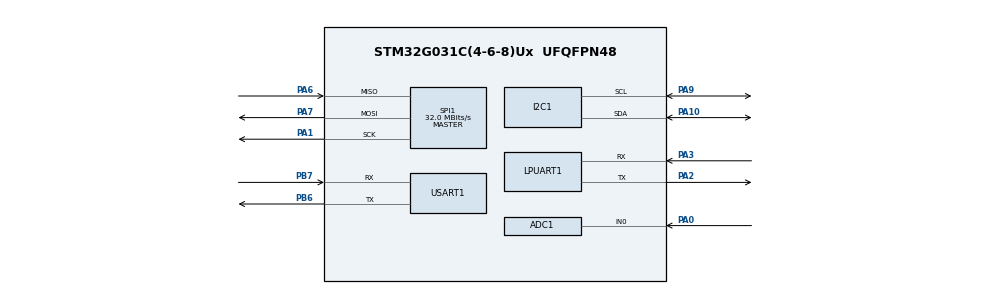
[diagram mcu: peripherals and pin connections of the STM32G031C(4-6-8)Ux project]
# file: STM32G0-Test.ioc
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ADC1.Channel-0\#ChannelRegularConversion=ADC_CHANNEL_0
ADC1.NbrOfConversionFlag=1
ADC1.Rank-0\#ChannelRegularConversion=1
ADC1.SamplingTime-0\#ChannelRegularConversion=ADC_SAMPLINGTIME_COMMON_1
ADC1.SelectedChannel=ADC_CHANNEL_0
ADC1.master=1
Dma.MEMTOMEM.0.Direction=DMA_MEMORY_TO_MEMORY
Dma.MEMTOMEM.0.EventEnable=DISABLE
Dma.MEMTOMEM.0.Instance=DMA1_Channel1
Dma.MEMTOMEM.0.MemDataAlignment=DMA_MDATAALIGN_BYTE
Dma.MEMTOMEM.0.MemInc=DMA_MINC_ENABLE
Dma.MEMTOMEM.0.Mode=DMA_NORMAL
Dma.MEMTOMEM.0.PeriphDataAlignment=DMA_PDATAALIGN_BYTE
Dma.MEMTOMEM.0.PeriphInc=DMA_PINC_ENABLE
Dma.MEMTOMEM.0.Polarity=HAL_DMAMUX_REQ_GEN_RISING
Dma.MEMTOMEM.0.Priority=DMA_PRIORITY_LOW
Dma.MEMTOMEM.0.RequestNumber=1
Dma.MEMTOMEM.0.SignalID=NONE
Dma.MEMTOMEM.0.SyncEnable=DISABLE
Dma.MEMTOMEM.0.SyncPolarity=HAL_DMAMUX_SYNC_NO_EVENT
Dma.MEMTOMEM.0.SyncRequestNumber=1
Dma.MEMTOMEM.0.SyncSignalID=NONE
Dma.Request0=MEMTOMEM
I2C1.Timing=0x10707DBC
Mcu.Family=STM32G0
Mcu.Name=STM32G031C(4-6-8)Ux
Mcu.Package=UFQFPN48
PA0.Mode=IN0
PA0.Signal=ADC1_IN0
PA1.Mode=Full_Duplex_Master
PA1.Signal=SPI1_SCK
PA10.Mode=I2C
PA10.Signal=I2C1_SDA
PA2.Mode=Asynchronous
PA2.Signal=LPUART1_TX
PA3.Mode=Asynchronous
PA3.Signal=LPUART1_RX
PA6.Mode=Full_Duplex_Master
PA6.Signal=SPI1_MISO
PA7.Mode=Full_Duplex_Master
PA7.Signal=SPI1_MOSI
PA9.Mode=I2C
PA9.Signal=I2C1_SCL
PB6.Mode=Asynchronous
PB6.Signal=USART1_TX
PB7.Mode=Asynchronous
PB7.Signal=USART1_RX
PF0-OSC_IN\ (PF0).Mode=HSE-External-Oscillator
PF0-OSC_IN\ (PF0).Signal=RCC_OSC_IN
PF1-OSC_OUT\ (PF1).Mode=HSE-External-Oscillator
PF1-OSC_OUT\ (PF1).Signal=RCC_OSC_OUT
ProjectManager.HeapSize=0x200
ProjectManager.StackSize=0x400
ProjectManager.TargetToolchain=STM32CubeIDE
RCC.ADCCLockSelection=RCC_ADCCLKSOURCE_HSI
RCC.ADCFreq_Value=16000000
RCC.AHBFreq_Value=64000000
RCC.CortexFreq_Value=64000000
RCC.EXTERNAL_CLOCK_VALUE=12288000
RCC.HCLKFreq_Value=64000000
RCC.HSE_VALUE=8000000
RCC.HSI_VALUE=16000000
RCC.LSE_VALUE=32768
RCC.SYSCLKFreq_VALUE=64000000
RCC.SYSCLKSource=RCC_SYSCLKSOURCE_PLLCLK
RCC.VCOOutputFreq_Value=128000000
SPI1.CalculateBaudRate=32.0 MBits/s
SPI1.Direction=SPI_DIRECTION_2LINES
SPI1.Mode=SPI_MODE_MASTER
SPI1.VirtualType=VM_MASTER
USART1.VirtualMode-Asynchronous=VM_ASYNC
VP_CRC_VS_CRC.Mode=CRC_Activate
VP_IWDG_VS_IWDG.Mode=IWDG_Activate
VP_RTC_VS_RTC_Activate.Mode=RTC_Enabled
VP_TIM1_VS_ClockSourceINT.Mode=Internal
VP_TIM1_VS_ClockSourceITR.Mode=TriggerSource_ITR0
VP_TIM1_VS_ControllerModeReset.Mode=Reset Mode
board=custom

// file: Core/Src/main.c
/* USER CODE BEGIN Header */
/**
  ******************************************************************************
  * @file           : main.c
  * @brief          : Main program body
  ******************************************************************************
  * @attention
  *
  * Copyright (c) 2022 STMicroelectronics.
  * All rights reserved.
  *
  * This software is licensed under terms that can be found in the LICENSE file
  * in the root directory of this software component.
  * If no LICENSE file comes with this software, it is provided AS-IS.
  *
  ******************************************************************************
  */
/* USER CODE END Header */
#include "main.h"

ADC_HandleTypeDef hadc1;

CRC_HandleTypeDef hcrc;

I2C_HandleTypeDef hi2c1;

IWDG_HandleTypeDef hiwdg;

UART_HandleTypeDef hlpuart1;
UART_HandleTypeDef huart1;

RTC_HandleTypeDef hrtc;

SPI_HandleTypeDef hspi1;

TIM_HandleTypeDef htim1;

DMA_HandleTypeDef hdma_memtomem_dma1_channel1;

void SystemClock_Config(void);
static void MX_DMA_Init(void);
static void MX_GPIO_Init(void);
static void MX_ADC1_Init(void);
static void MX_CRC_Init(void);
static void MX_I2C1_Init(void);
static void MX_IWDG_Init(void);
static void MX_LPUART1_UART_Init(void);
static void MX_USART1_UART_Init(void);
static void MX_RTC_Init(void);
static void MX_SPI1_Init(void);
static void MX_TIM1_Init(void);

int main(void)
{

  /* MCU Configuration--------------------------------------------------------*/

  /* Reset of all peripherals, Initializes the Flash interface and the Systick. */
  HAL_Init();

  /* Configure the system clock */
  SystemClock_Config();

  /* Initialize all configured peripherals */
  MX_DMA_Init();
  MX_GPIO_Init();
  MX_ADC1_Init();
  MX_CRC_Init();
  MX_I2C1_Init();
  MX_IWDG_Init();
  MX_LPUART1_UART_Init();
  MX_USART1_UART_Init();
  MX_RTC_Init();
  MX_SPI1_Init();
  MX_TIM1_Init();

  /* Infinite loop */
  while (1)
  {

  }
}

void SystemClock_Config(void)
{
  RCC_OscInitTypeDef RCC_OscInitStruct = {0};
  RCC_ClkInitTypeDef RCC_ClkInitStruct = {0};

  /** Configure the main internal regulator output voltage
  */
  HAL_PWREx_ControlVoltageScaling(PWR_REGULATOR_VOLTAGE_SCALE1);
  /** Initializes the RCC Oscillators according to the specified parameters
  * in the RCC_OscInitTypeDef structure.
  */
  RCC_OscInitStruct.OscillatorType = RCC_OSCILLATORTYPE_HSI|RCC_OSCILLATORTYPE_LSI;
  RCC_OscInitStruct.HSIState = RCC_HSI_ON;
  RCC_OscInitStruct.HSIDiv = RCC_HSI_DIV1;
  RCC_OscInitStruct.HSICalibrationValue = RCC_HSICALIBRATION_DEFAULT;
  RCC_OscInitStruct.LSIState = RCC_LSI_ON;
  RCC_OscInitStruct.PLL.PLLState = RCC_PLL_NONE;
  if (HAL_RCC_OscConfig(&RCC_OscInitStruct) != HAL_OK)
  {
    Error_Handler();
  }
  /** Initializes the CPU, AHB and APB buses clocks
  */
  RCC_ClkInitStruct.ClockType = RCC_CLOCKTYPE_HCLK|RCC_CLOCKTYPE_SYSCLK
                              |RCC_CLOCKTYPE_PCLK1;
  RCC_ClkInitStruct.SYSCLKSource = RCC_SYSCLKSOURCE_HSI;
  RCC_ClkInitStruct.AHBCLKDivider = RCC_SYSCLK_DIV1;
  RCC_ClkInitStruct.APB1CLKDivider = RCC_HCLK_DIV1;

  if (HAL_RCC_ClockConfig(&RCC_ClkInitStruct, FLASH_LATENCY_0) != HAL_OK)
  {
    Error_Handler();
  }
}

static void MX_ADC1_Init(void)
{

  ADC_ChannelConfTypeDef sConfig = {0};

  /** Configure the global features of the ADC (Clock, Resolution, Data Alignment and number of conversion)
  */
  hadc1.Instance = ADC1;
  hadc1.Init.ClockPrescaler = ADC_CLOCK_SYNC_PCLK_DIV2;
  hadc1.Init.Resolution = ADC_RESOLUTION_12B;
  hadc1.Init.DataAlign = ADC_DATAALIGN_RIGHT;
  hadc1.Init.ScanConvMode = ADC_SCAN_DISABLE;
  hadc1.Init.EOCSelection = ADC_EOC_SINGLE_CONV;
  hadc1.Init.LowPowerAutoWait = DISABLE;
  hadc1.Init.LowPowerAutoPowerOff = DISABLE;
  hadc1.Init.ContinuousConvMode = DISABLE;
  hadc1.Init.NbrOfConversion = 1;
  hadc1.Init.DiscontinuousConvMode = DISABLE;
  hadc1.Init.ExternalTrigConv = ADC_SOFTWARE_START;
  hadc1.Init.ExternalTrigConvEdge = ADC_EXTERNALTRIGCONVEDGE_NONE;
  hadc1.Init.DMAContinuousRequests = DISABLE;
  hadc1.Init.Overrun = ADC_OVR_DATA_PRESERVED;
  hadc1.Init.SamplingTimeCommon1 = ADC_SAMPLETIME_1CYCLE_5;
  hadc1.Init.SamplingTimeCommon2 = ADC_SAMPLETIME_1CYCLE_5;
  hadc1.Init.OversamplingMode = DISABLE;
  hadc1.Init.TriggerFrequencyMode = ADC_TRIGGER_FREQ_HIGH;
  if (HAL_ADC_Init(&hadc1) != HAL_OK)
  {
    Error_Handler();
  }
  /** Configure Regular Channel
  */
  sConfig.Channel = ADC_CHANNEL_0;
  sConfig.Rank = ADC_REGULAR_RANK_1;
  sConfig.SamplingTime = ADC_SAMPLINGTIME_COMMON_1;
  if (HAL_ADC_ConfigChannel(&hadc1, &sConfig) != HAL_OK)
  {
    Error_Handler();
  }

}

static void MX_CRC_Init(void)
{

  hcrc.Instance = CRC;
  hcrc.Init.DefaultPolynomialUse = DEFAULT_POLYNOMIAL_ENABLE;
  hcrc.Init.DefaultInitValueUse = DEFAULT_INIT_VALUE_ENABLE;
  hcrc.Init.InputDataInversionMode = CRC_INPUTDATA_INVERSION_NONE;
  hcrc.Init.OutputDataInversionMode = CRC_OUTPUTDATA_INVERSION_DISABLE;
  hcrc.InputDataFormat = CRC_INPUTDATA_FORMAT_BYTES;
  if (HAL_CRC_Init(&hcrc) != HAL_OK)
  {
    Error_Handler();
  }

}

static void MX_I2C1_Init(void)
{

  hi2c1.Instance = I2C1;
  hi2c1.Init.Timing = 0x00303D5B;
  hi2c1.Init.OwnAddress1 = 0;
  hi2c1.Init.AddressingMode = I2C_ADDRESSINGMODE_7BIT;
  hi2c1.Init.DualAddressMode = I2C_DUALADDRESS_DISABLE;
  hi2c1.Init.OwnAddress2 = 0;
  hi2c1.Init.OwnAddress2Masks = I2C_OA2_NOMASK;
  hi2c1.Init.GeneralCallMode = I2C_GENERALCALL_DISABLE;
  hi2c1.Init.NoStretchMode = I2C_NOSTRETCH_DISABLE;
  if (HAL_I2C_Init(&hi2c1) != HAL_OK)
  {
    Error_Handler();
  }
  /** Configure Analogue filter
  */
  if (HAL_I2CEx_ConfigAnalogFilter(&hi2c1, I2C_ANALOGFILTER_ENABLE) != HAL_OK)
  {
    Error_Handler();
  }
  /** Configure Digital filter
  */
  if (HAL_I2CEx_ConfigDigitalFilter(&hi2c1, 0) != HAL_OK)
  {
    Error_Handler();
  }

}

static void MX_IWDG_Init(void)
{

  hiwdg.Instance = IWDG;
  hiwdg.Init.Prescaler = IWDG_PRESCALER_4;
  hiwdg.Init.Window = 4095;
  hiwdg.Init.Reload = 4095;
  if (HAL_IWDG_Init(&hiwdg) != HAL_OK)
  {
    Error_Handler();
  }

}

static void MX_LPUART1_UART_Init(void)
{

  hlpuart1.Instance = LPUART1;
  hlpuart1.Init.BaudRate = 209700;
  hlpuart1.Init.WordLength = UART_WORDLENGTH_7B;
  hlpuart1.Init.StopBits = UART_STOPBITS_1;
  hlpuart1.Init.Parity = UART_PARITY_NONE;
  hlpuart1.Init.Mode = UART_MODE_TX_RX;
  hlpuart1.Init.HwFlowCtl = UART_HWCONTROL_NONE;
  hlpuart1.Init.OneBitSampling = UART_ONE_BIT_SAMPLE_DISABLE;
  hlpuart1.Init.ClockPrescaler = UART_PRESCALER_DIV1;
  hlpuart1.AdvancedInit.AdvFeatureInit = UART_ADVFEATURE_NO_INIT;
  hlpuart1.FifoMode = UART_FIFOMODE_DISABLE;
  if (HAL_UART_Init(&hlpuart1) != HAL_OK)
  {
    Error_Handler();
  }
  if (HAL_UARTEx_SetTxFifoThreshold(&hlpuart1, UART_TXFIFO_THRESHOLD_1_8) != HAL_OK)
  {
    Error_Handler();
  }
  if (HAL_UARTEx_SetRxFifoThreshold(&hlpuart1, UART_RXFIFO_THRESHOLD_1_8) != HAL_OK)
  {
    Error_Handler();
  }
  if (HAL_UARTEx_DisableFifoMode(&hlpuart1) != HAL_OK)
  {
    Error_Handler();
  }

}

static void MX_USART1_UART_Init(void)
{

  huart1.Instance = USART1;
  huart1.Init.BaudRate = 115200;
  huart1.Init.WordLength = UART_WORDLENGTH_8B;
  huart1.Init.StopBits = UART_STOPBITS_1;
  huart1.Init.Parity = UART_PARITY_NONE;
  huart1.Init.Mode = UART_MODE_TX_RX;
  huart1.Init.HwFlowCtl = UART_HWCONTROL_NONE;
  huart1.Init.OverSampling = UART_OVERSAMPLING_16;
  huart1.Init.OneBitSampling = UART_ONE_BIT_SAMPLE_DISABLE;
  huart1.Init.ClockPrescaler = UART_PRESCALER_DIV1;
  huart1.AdvancedInit.AdvFeatureInit = UART_ADVFEATURE_NO_INIT;
  if (HAL_UART_Init(&huart1) != HAL_OK)
  {
    Error_Handler();
  }
  if (HAL_UARTEx_SetTxFifoThreshold(&huart1, UART_TXFIFO_THRESHOLD_1_8) != HAL_OK)
  {
    Error_Handler();
  }
  if (HAL_UARTEx_SetRxFifoThreshold(&huart1, UART_RXFIFO_THRESHOLD_1_8) != HAL_OK)
  {
    Error_Handler();
  }
  if (HAL_UARTEx_DisableFifoMode(&huart1) != HAL_OK)
  {
    Error_Handler();
  }

}

static void MX_RTC_Init(void)
{

  /** Initialize RTC Only
  */
  hrtc.Instance = RTC;
  hrtc.Init.HourFormat = RTC_HOURFORMAT_24;
  hrtc.Init.AsynchPrediv = 127;
  hrtc.Init.SynchPrediv = 255;
  hrtc.Init.OutPut = RTC_OUTPUT_DISABLE;
  hrtc.Init.OutPutRemap = RTC_OUTPUT_REMAP_NONE;
  hrtc.Init.OutPutPolarity = RTC_OUTPUT_POLARITY_HIGH;
  hrtc.Init.OutPutType = RTC_OUTPUT_TYPE_OPENDRAIN;
  hrtc.Init.OutPutPullUp = RTC_OUTPUT_PULLUP_NONE;
  if (HAL_RTC_Init(&hrtc) != HAL_OK)
  {
    Error_Handler();
  }

}

static void MX_SPI1_Init(void)
{

  /* SPI1 parameter configuration*/
  hspi1.Instance = SPI1;
  hspi1.Init.Mode = SPI_MODE_MASTER;
  hspi1.Init.Direction = SPI_DIRECTION_2LINES;
  hspi1.Init.DataSize = SPI_DATASIZE_8BIT;
  hspi1.Init.CLKPolarity = SPI_POLARITY_LOW;
  hspi1.Init.CLKPhase = SPI_PHASE_1EDGE;
  hspi1.Init.NSS = SPI_NSS_SOFT;
  hspi1.Init.BaudRatePrescaler = SPI_BAUDRATEPRESCALER_2;
  hspi1.Init.FirstBit = SPI_FIRSTBIT_MSB;
  hspi1.Init.TIMode = SPI_TIMODE_DISABLE;
  hspi1.Init.CRCCalculation = SPI_CRCCALCULATION_DISABLE;
  hspi1.Init.CRCPolynomial = 7;
  hspi1.Init.CRCLength = SPI_CRC_LENGTH_DATASIZE;
  hspi1.Init.NSSPMode = SPI_NSS_PULSE_ENABLE;
  if (HAL_SPI_Init(&hspi1) != HAL_OK)
  {
    Error_Handler();
  }

}

static void MX_TIM1_Init(void)
{

  TIM_ClockConfigTypeDef sClockSourceConfig = {0};
  TIM_SlaveConfigTypeDef sSlaveConfig = {0};
  TIM_MasterConfigTypeDef sMasterConfig = {0};

  htim1.Instance = TIM1;
  htim1.Init.Prescaler = 0;
  htim1.Init.CounterMode = TIM_COUNTERMODE_UP;
  htim1.Init.Period = 65535;
  htim1.Init.ClockDivision = TIM_CLOCKDIVISION_DIV1;
  htim1.Init.RepetitionCounter = 0;
  htim1.Init.AutoReloadPreload = TIM_AUTORELOAD_PRELOAD_DISABLE;
  if (HAL_TIM_Base_Init(&htim1) != HAL_OK)
  {
    Error_Handler();
  }
  sClockSourceConfig.ClockSource = TIM_CLOCKSOURCE_INTERNAL;
  if (HAL_TIM_ConfigClockSource(&htim1, &sClockSourceConfig) != HAL_OK)
  {
    Error_Handler();
  }
  sSlaveConfig.SlaveMode = TIM_SLAVEMODE_RESET;
  sSlaveConfig.InputTrigger = TIM_TS_ITR0;
  if (HAL_TIM_SlaveConfigSynchro(&htim1, &sSlaveConfig) != HAL_OK)
  {
    Error_Handler();
  }
  sMasterConfig.MasterOutputTrigger = TIM_TRGO_RESET;
  sMasterConfig.MasterOutputTrigger2 = TIM_TRGO2_RESET;
  sMasterConfig.MasterSlaveMode = TIM_MASTERSLAVEMODE_DISABLE;
  if (HAL_TIMEx_MasterConfigSynchronization(&htim1, &sMasterConfig) != HAL_OK)
  {
    Error_Handler();
  }

}

static void MX_DMA_Init(void)
{

  /* DMA controller clock enable */
  __HAL_RCC_DMA1_CLK_ENABLE();

  /* Configure DMA request hdma_memtomem_dma1_channel1 on DMA1_Channel1 */
  hdma_memtomem_dma1_channel1.Instance = DMA1_Channel1;
  hdma_memtomem_dma1_channel1.Init.Request = DMA_REQUEST_MEM2MEM;
  hdma_memtomem_dma1_channel1.Init.Direction = DMA_MEMORY_TO_MEMORY;
  hdma_memtomem_dma1_channel1.Init.PeriphInc = DMA_PINC_ENABLE;
  hdma_memtomem_dma1_channel1.Init.MemInc = DMA_MINC_ENABLE;
  hdma_memtomem_dma1_channel1.Init.PeriphDataAlignment = DMA_PDATAALIGN_BYTE;
  hdma_memtomem_dma1_channel1.Init.MemDataAlignment = DMA_MDATAALIGN_BYTE;
  hdma_memtomem_dma1_channel1.Init.Mode = DMA_NORMAL;
  hdma_memtomem_dma1_channel1.Init.Priority = DMA_PRIORITY_LOW;
  if (HAL_DMA_Init(&hdma_memtomem_dma1_channel1) != HAL_OK)
  {
    Error_Handler( );
  }

}

static void MX_GPIO_Init(void)
{

  /* GPIO Ports Clock Enable */
  __HAL_RCC_GPIOF_CLK_ENABLE();
  __HAL_RCC_GPIOA_CLK_ENABLE();
  __HAL_RCC_GPIOB_CLK_ENABLE();

}

void Error_Handler(void)
{
  __disable_irq();
  while (1)
  {
  }
}
